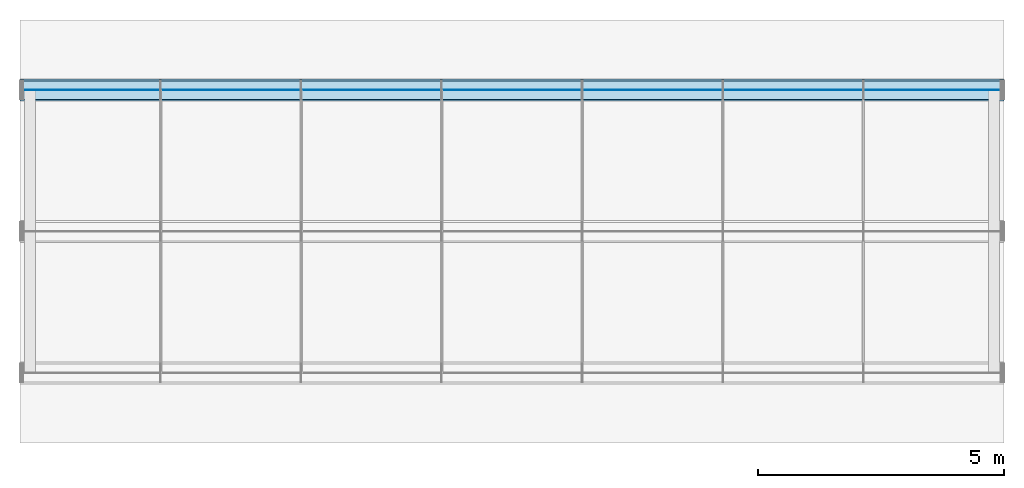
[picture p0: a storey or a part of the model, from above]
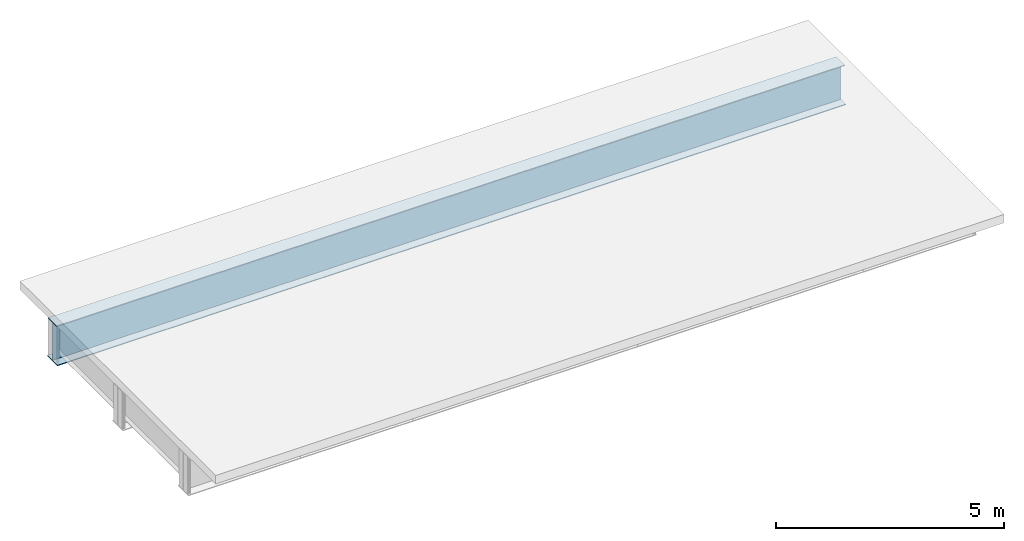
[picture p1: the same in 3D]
Properties of the parts of a building model (IFC4)

# File
Description: ViewDefinition [CoordinationView]
Time: 2026-06-10T15:59:33
Written by: IfcOpenShell 0.8.0
Made in: IfcOpenShell 0.8.0

# IfcMember (52)
In: Superstructure
Pset_OsdagBridgeProperties - Material: E250
Name | ProfileDepth_or_LegHeight | ProfileWidth_or_LegWidth | ConnectionType
4 x End Diaphragm | 0.808 | 0.225 | Pset_OsdagBridgeProperties - WebThickness: 0.012; FlangeThickness: 0.012
24 x Diagonal Brace | 0.075 | 0.05 | LONGER_LEG | Pset_OsdagBridgeProperties - ComponentRole: Intermediate Bracing Diagonal; BracingPattern: X; ProfileType: ANGLE; ProfileThickness: 0.008; StructuralSystem: Intermediate Bracing
12 x Bottom Chord |  |  | LONGER_LEG
12 x Top Chord |  |  | LONGER_LEG

# IfcPlate (69)
In: Superstructure
Pset_OsdagBridgeProperties - Material: E250
Name | ComponentRole | Thickness | Spacing
Girder Web 1 | Girder Web | 0.012 | Pset_OsdagBridgeProperties - SpanLength: 20; GirderSpacing: 2.875; Depth: 1.01
Top Flange 1 | Main Girder | Pset_OsdagBridgeProperties - SpanLength: 20; GirderSpacing: 2.875
Bottom Flange 1 | Main Girder | Pset_OsdagBridgeProperties - SpanLength: 20; GirderSpacing: 2.875
Girder Web 2 | Girder Web | 0.012 | Pset_OsdagBridgeProperties - SpanLength: 20; GirderSpacing: 2.875; Depth: 1.01
Top Flange 2 | Main Girder | Pset_OsdagBridgeProperties - SpanLength: 20; GirderSpacing: 2.875
Bottom Flange 2 | Main Girder | Pset_OsdagBridgeProperties - SpanLength: 20; GirderSpacing: 2.875
Girder Web 3 | Girder Web | 0.012 | Pset_OsdagBridgeProperties - SpanLength: 20; GirderSpacing: 2.875; Depth: 1.01
Top Flange 3 | Main Girder | Pset_OsdagBridgeProperties - SpanLength: 20; GirderSpacing: 2.875
Bottom Flange 3 | Main Girder | Pset_OsdagBridgeProperties - SpanLength: 20; GirderSpacing: 2.875
12 x Intermediate Stiffener 1 | Intermediate Stiffener | 0.012 | 2.857
8 x End Stiffener 1 | End Stiffener | 0.02
12 x Intermediate Stiffener 2 | Intermediate Stiffener | 0.012 | 2.857
8 x End Stiffener 2 | End Stiffener | 0.02
12 x Intermediate Stiffener 3 | Intermediate Stiffener | 0.012 | 2.857
8 x End Stiffener 3 | End Stiffener | 0.02

# IfcSlab, Deck Slab
In: Superstructure
Pset_OsdagBridgeProperties - ComponentRole: Deck Slab; DeckThickness: 0.23; CarriagewayWidth: 7.5; SpanLength: 20; SkewAngle: 0; Material: M30; fck_MPa: 30; fctm_MPa: 2.5; Ecm_GPa: 31
